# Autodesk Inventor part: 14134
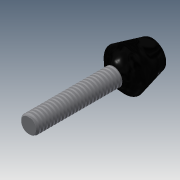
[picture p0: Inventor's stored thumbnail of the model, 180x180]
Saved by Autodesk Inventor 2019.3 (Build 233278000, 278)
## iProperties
Created: 2017-06
Part Number: 14134
Material: Ogólny
Document SubType Name: Modeling
Designer: CADENGINEERING4
Density: 1 g/cm^3
Appearance: Domyślna
Author: CADENGINEERING4
Revision Number: ÈÎºÎ
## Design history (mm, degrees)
feature "NONE"
node "Bryła1"
